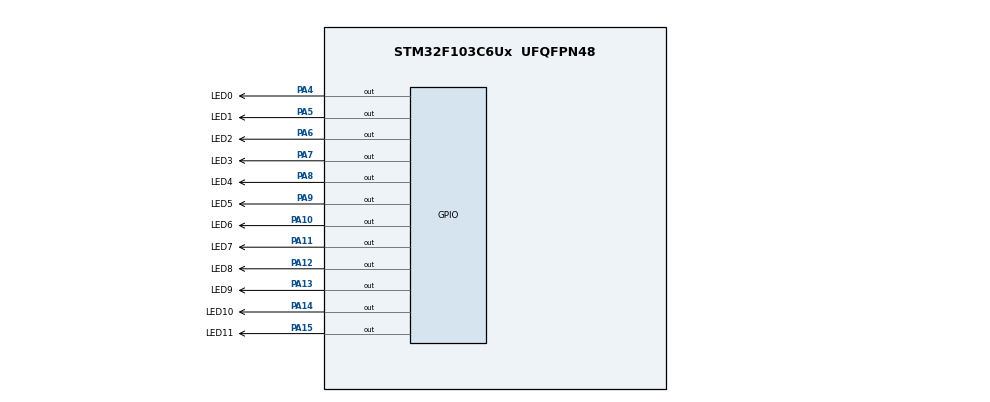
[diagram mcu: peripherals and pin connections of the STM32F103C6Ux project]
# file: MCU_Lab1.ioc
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Mcu.Family=STM32F1
Mcu.Name=STM32F103C6Ux
Mcu.Package=UFQFPN48
NVIC.PriorityGroup=NVIC_PRIORITYGROUP_4
PA10.GPIO_Label=LED6
PA10.Signal=GPIO_Output
PA11.GPIO_Label=LED7
PA11.Signal=GPIO_Output
PA12.GPIO_Label=LED8
PA12.Signal=GPIO_Output
PA13.GPIO_Label=LED9
PA13.Signal=GPIO_Output
PA14.GPIO_Label=LED10
PA14.Signal=GPIO_Output
PA15.GPIO_Label=LED11
PA15.Signal=GPIO_Output
PA4.GPIO_Label=LED0
PA4.Signal=GPIO_Output
PA5.GPIO_Label=LED1
PA5.Signal=GPIO_Output
PA6.GPIO_Label=LED2
PA6.Signal=GPIO_Output
PA7.GPIO_Label=LED3
PA7.Signal=GPIO_Output
PA8.GPIO_Label=LED4
PA8.Signal=GPIO_Output
PA9.GPIO_Label=LED5
PA9.Signal=GPIO_Output
ProjectManager.HeapSize=0x200
ProjectManager.StackSize=0x400
ProjectManager.TargetToolchain=STM32CubeIDE
RCC.APB1Freq_Value=8000000
RCC.APB2Freq_Value=8000000
VP_SYS_VS_ND.Mode=No_Debug
board=custom

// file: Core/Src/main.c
/* USER CODE BEGIN Header */
/**
  ******************************************************************************
  * @file           : main.c
  * @brief          : Main program body
  ******************************************************************************
  * @attention
  *
  * <h2><center>&copy; Copyright (c) 2023 STMicroelectronics.
  * All rights reserved.</center></h2>
  *
  * This software component is licensed by ST under BSD 3-Clause license,
  * the "License"; You may not use this file except in compliance with the
  * License. You may obtain a copy of the License at:
  *                        opensource.org/licenses/BSD-3-Clause
  *
  ******************************************************************************
  */
/* USER CODE END Header */
#include "main.h"

void SystemClock_Config(void);
static void MX_GPIO_Init(void);
/* USER CODE BEGIN PFP */
void display7SEG(int num){
	if(num==1 || num==4) HAL_GPIO_WritePin (SEG7_A_GPIO_Port, SEG7_A_Pin, SET);
	else HAL_GPIO_WritePin (SEG7_A_GPIO_Port, SEG7_A_Pin, RESET);

	if(num==5 || num==6) HAL_GPIO_WritePin (SEG7_B_GPIO_Port, SEG7_B_Pin, SET);
	else HAL_GPIO_WritePin (SEG7_B_GPIO_Port, SEG7_B_Pin, RESET);

	if(num==2) HAL_GPIO_WritePin (SEG7_C_GPIO_Port, SEG7_C_Pin, SET);
	else HAL_GPIO_WritePin (SEG7_C_GPIO_Port, SEG7_C_Pin, RESET);

	if(num==1 || num==4 || num==7) HAL_GPIO_WritePin (SEG7_D_GPIO_Port, SEG7_D_Pin, SET);
	else HAL_GPIO_WritePin (SEG7_D_GPIO_Port, SEG7_D_Pin, RESET);

	if(num==1 || num==3 || num==4 || num==5 || num==7 || num==9) HAL_GPIO_WritePin (SEG7_E_GPIO_Port, SEG7_E_Pin, SET);
	else HAL_GPIO_WritePin (SEG7_E_GPIO_Port, SEG7_E_Pin, RESET);

	if(num==1 || num==2 || num==3 || num==7) HAL_GPIO_WritePin (SEG7_F_GPIO_Port, SEG7_F_Pin, SET);
	else HAL_GPIO_WritePin (SEG7_F_GPIO_Port, SEG7_F_Pin, RESET);

	if(num==0 || num==1 || num==7) HAL_GPIO_WritePin (SEG7_G_GPIO_Port, SEG7_G_Pin, SET);
	else HAL_GPIO_WritePin (SEG7_G_GPIO_Port, SEG7_G_Pin, RESET);

}
/* USER CODE END PFP */

int main(void)
{

  /* MCU Configuration--------------------------------------------------------*/

  /* Reset of all peripherals, Initializes the Flash interface and the Systick. */
  HAL_Init();

  /* Configure the system clock */
  SystemClock_Config();

  /* Initialize all configured peripherals */
  MX_GPIO_Init();

  /* Infinite loop */
  /* USER CODE BEGIN WHILE */
  int sec = 3;
  int currentState = 0;
  while (1)
  {
	  display7SEG(sec);
	  if(currentState==0){
		  HAL_GPIO_WritePin(LED_RED_GPIO_Port, LED_RED_Pin, SET);
		  HAL_GPIO_WritePin(LED_YELLOW_GPIO_Port, LED_YELLOW_Pin, SET);
		  HAL_GPIO_WritePin(LED_GREEN_GPIO_Port, LED_GREEN_Pin, RESET);

		  HAL_GPIO_WritePin(LED_RED2_GPIO_Port, LED_RED2_Pin, RESET);
		  HAL_GPIO_WritePin(LED_YELLOW2_GPIO_Port, LED_YELLOW2_Pin, SET);
		  HAL_GPIO_WritePin(LED_GREEN2_GPIO_Port, LED_GREEN2_Pin, SET);

		  sec--;
		  if(sec<=0){
			  currentState = 1;
			  sec=2;
		  }
	  }
	  else if(currentState==1){
		  HAL_GPIO_WritePin(LED_RED_GPIO_Port, LED_RED_Pin, SET);
		  HAL_GPIO_WritePin(LED_YELLOW_GPIO_Port, LED_YELLOW_Pin, RESET);
		  HAL_GPIO_WritePin(LED_GREEN_GPIO_Port, LED_GREEN_Pin, SET);

		  HAL_GPIO_WritePin(LED_RED2_GPIO_Port, LED_RED2_Pin, RESET);
		  HAL_GPIO_WritePin(LED_YELLOW2_GPIO_Port, LED_YELLOW2_Pin, SET);
		  HAL_GPIO_WritePin(LED_GREEN2_GPIO_Port, LED_GREEN2_Pin, SET);

		  sec--;
		  if(sec<=0){
			  currentState = 2;
			  sec=5;
		  }
	  }
	  else if(currentState==2){
		  HAL_GPIO_WritePin(LED_RED_GPIO_Port, LED_RED_Pin, RESET);
		  HAL_GPIO_WritePin(LED_YELLOW_GPIO_Port, LED_YELLOW_Pin, SET);
		  HAL_GPIO_WritePin(LED_GREEN_GPIO_Port, LED_GREEN_Pin, SET);

		  HAL_GPIO_WritePin(LED_RED2_GPIO_Port, LED_RED2_Pin, SET);
		  HAL_GPIO_WritePin(LED_YELLOW2_GPIO_Port, LED_YELLOW2_Pin, SET);
		  HAL_GPIO_WritePin(LED_GREEN2_GPIO_Port, LED_GREEN2_Pin, RESET);

		  sec--;
		  if(sec==2){
			  currentState = 3;
		  }
	  }
	  else if(currentState==3){
		  HAL_GPIO_WritePin(LED_RED2_GPIO_Port, LED_RED2_Pin, SET);
		  HAL_GPIO_WritePin(LED_YELLOW2_GPIO_Port, LED_YELLOW2_Pin, RESET);
		  HAL_GPIO_WritePin(LED_GREEN2_GPIO_Port, LED_GREEN2_Pin, SET);

		  sec--;
		  if(sec<=0){
			  currentState = 0;
			  sec=3;
		  }
	  }

	  HAL_Delay (1000) ;
    /* USER CODE END WHILE */

  }
}

void SystemClock_Config(void)
{
  RCC_OscInitTypeDef RCC_OscInitStruct = {0};
  RCC_ClkInitTypeDef RCC_ClkInitStruct = {0};

  /** Initializes the RCC Oscillators according to the specified parameters
  * in the RCC_OscInitTypeDef structure.
  */
  RCC_OscInitStruct.OscillatorType = RCC_OSCILLATORTYPE_HSI;
  RCC_OscInitStruct.HSIState = RCC_HSI_ON;
  RCC_OscInitStruct.HSICalibrationValue = RCC_HSICALIBRATION_DEFAULT;
  RCC_OscInitStruct.PLL.PLLState = RCC_PLL_NONE;
  if (HAL_RCC_OscConfig(&RCC_OscInitStruct) != HAL_OK)
  {
    Error_Handler();
  }
  /** Initializes the CPU, AHB and APB buses clocks
  */
  RCC_ClkInitStruct.ClockType = RCC_CLOCKTYPE_HCLK|RCC_CLOCKTYPE_SYSCLK
                              |RCC_CLOCKTYPE_PCLK1|RCC_CLOCKTYPE_PCLK2;
  RCC_ClkInitStruct.SYSCLKSource = RCC_SYSCLKSOURCE_HSI;
  RCC_ClkInitStruct.AHBCLKDivider = RCC_SYSCLK_DIV1;
  RCC_ClkInitStruct.APB1CLKDivider = RCC_HCLK_DIV1;
  RCC_ClkInitStruct.APB2CLKDivider = RCC_HCLK_DIV1;

  if (HAL_RCC_ClockConfig(&RCC_ClkInitStruct, FLASH_LATENCY_0) != HAL_OK)
  {
    Error_Handler();
  }
}

static void MX_GPIO_Init(void)
{
  GPIO_InitTypeDef GPIO_InitStruct = {0};

  /* GPIO Ports Clock Enable */
  __HAL_RCC_GPIOA_CLK_ENABLE();
  __HAL_RCC_GPIOB_CLK_ENABLE();

  /*Configure GPIO pin Output Level */
  HAL_GPIO_WritePin(GPIOA, LED_RED_Pin|LED_YELLOW_Pin|LED_GREEN_Pin|LED_RED2_Pin
                          |LED_YELLOW2_Pin|LED_GREEN2_Pin, GPIO_PIN_RESET);

  /*Configure GPIO pin Output Level */
  HAL_GPIO_WritePin(GPIOB, SEG7_A_Pin|SEG7_B_Pin|SEG7_C_Pin|SEG7_D_Pin
                          |SEG7_E_Pin|SEG7_F_Pin|SEG7_G_Pin, GPIO_PIN_RESET);

  /*Configure GPIO pins : LED_RED_Pin LED_YELLOW_Pin LED_GREEN_Pin LED_RED2_Pin
                           LED_YELLOW2_Pin LED_GREEN2_Pin */
  GPIO_InitStruct.Pin = LED_RED_Pin|LED_YELLOW_Pin|LED_GREEN_Pin|LED_RED2_Pin
                          |LED_YELLOW2_Pin|LED_GREEN2_Pin;
  GPIO_InitStruct.Mode = GPIO_MODE_OUTPUT_PP;
  GPIO_InitStruct.Pull = GPIO_NOPULL;
  GPIO_InitStruct.Speed = GPIO_SPEED_FREQ_LOW;
  HAL_GPIO_Init(GPIOA, &GPIO_InitStruct);

  /*Configure GPIO pins : SEG7_A_Pin SEG7_B_Pin SEG7_C_Pin SEG7_D_Pin
                           SEG7_E_Pin SEG7_F_Pin SEG7_G_Pin */
  GPIO_InitStruct.Pin = SEG7_A_Pin|SEG7_B_Pin|SEG7_C_Pin|SEG7_D_Pin
                          |SEG7_E_Pin|SEG7_F_Pin|SEG7_G_Pin;
  GPIO_InitStruct.Mode = GPIO_MODE_OUTPUT_PP;
  GPIO_InitStruct.Pull = GPIO_NOPULL;
  GPIO_InitStruct.Speed = GPIO_SPEED_FREQ_LOW;
  HAL_GPIO_Init(GPIOB, &GPIO_InitStruct);

}

void Error_Handler(void)
{
  __disable_irq();
  while (1)
  {
  }
}

/************************ (C) COPYRIGHT STMicroelectronics *****END OF FILE****/
